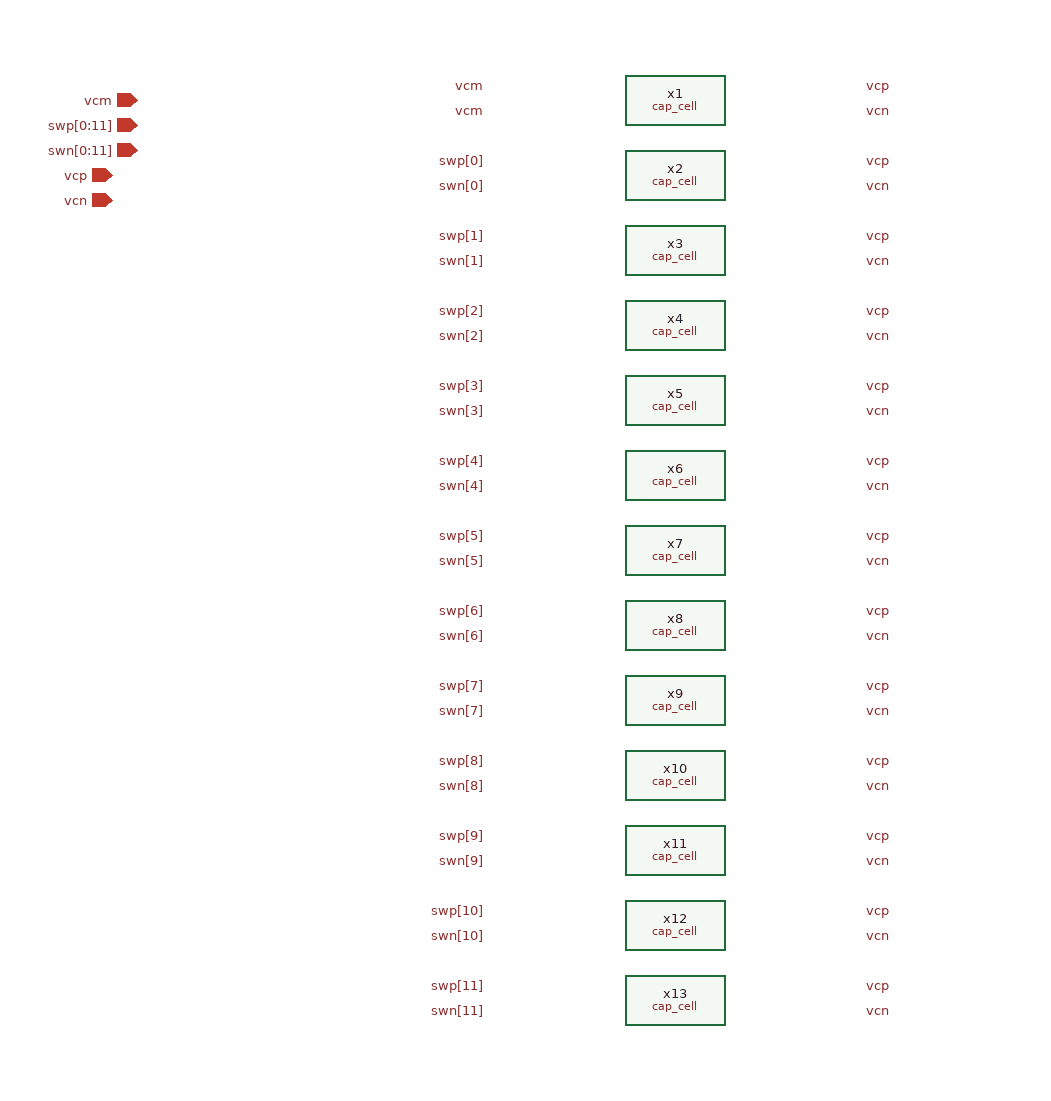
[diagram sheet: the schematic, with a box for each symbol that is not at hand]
v {xschem version=3.4.5 file_version=1.2
}
G {}
K {}
V {}
S {}
E {}
C {cap_cell.sym} 650 -880 0 0 {name=x1 dim=dim_unit num=1}
C {cap_cell.sym} 650 -820 0 0 {name=x2 dim=dim_unit num=1}
C {cap_cell.sym} 650 -760 0 0 {name=x3 dim=dim_unit num=2}
C {cap_cell.sym} 650 -700 0 0 {name=x4 dim=dim_unit num=4}
C {cap_cell.sym} 650 -640 0 0 {name=x5 dim=dim_unit num=8}
C {cap_cell.sym} 650 -580 0 0 {name=x6 dim=dim_unit num=16}
C {cap_cell.sym} 650 -520 0 0 {name=x7 dim=dim_unit num=32}
C {cap_cell.sym} 650 -460 0 0 {name=x8 dim=dim_unit num=64}
C {cap_cell.sym} 650 -400 0 0 {name=x9 dim=dim_unit num=128}
C {cap_cell.sym} 650 -340 0 0 {name=x10 dim=dim_unit num=256}
C {cap_cell.sym} 650 -280 0 0 {name=x11 dim=dim_unit num=512}
C {cap_cell.sym} 650 -220 0 0 {name=x12 dim=dim_unit num=1024}
C {cap_cell.sym} 650 -160 0 0 {name=x13 dim=dim_unit num=2048}
C {lab_wire.sym} 500 -890 0 0 {name=p1 sig_type=std_logic lab=vcm}
C {lab_wire.sym} 500 -870 0 0 {name=p2 sig_type=std_logic lab=vcm}
C {lab_wire.sym} 500 -830 0 0 {name=p3 sig_type=std_logic lab=swp[0]}
C {lab_wire.sym} 500 -810 0 0 {name=p4 sig_type=std_logic lab=swn[0]}
C {lab_wire.sym} 500 -770 0 0 {name=p5 sig_type=std_logic lab=swp[1]}
C {lab_wire.sym} 500 -750 0 0 {name=p6 sig_type=std_logic lab=swn[1]}
C {lab_wire.sym} 500 -710 0 0 {name=p7 sig_type=std_logic lab=swp[2]}
C {lab_wire.sym} 500 -690 0 0 {name=p8 sig_type=std_logic lab=swn[2]}
C {lab_wire.sym} 500 -650 0 0 {name=p9 sig_type=std_logic lab=swp[3]}
C {lab_wire.sym} 500 -630 0 0 {name=p10 sig_type=std_logic lab=swn[3]}
C {lab_wire.sym} 500 -590 0 0 {name=p11 sig_type=std_logic lab=swp[4]}
C {lab_wire.sym} 500 -570 0 0 {name=p12 sig_type=std_logic lab=swn[4]}
C {lab_wire.sym} 500 -530 0 0 {name=p13 sig_type=std_logic lab=swp[5]}
C {lab_wire.sym} 500 -510 0 0 {name=p14 sig_type=std_logic lab=swn[5]}
C {lab_wire.sym} 500 -470 0 0 {name=p15 sig_type=std_logic lab=swp[6]}
C {lab_wire.sym} 500 -450 0 0 {name=p16 sig_type=std_logic lab=swn[6]}
C {lab_wire.sym} 500 -410 0 0 {name=p17 sig_type=std_logic lab=swp[7]}
C {lab_wire.sym} 500 -390 0 0 {name=p18 sig_type=std_logic lab=swn[7]}
C {lab_wire.sym} 500 -350 0 0 {name=p19 sig_type=std_logic lab=swp[8]}
C {lab_wire.sym} 500 -330 0 0 {name=p20 sig_type=std_logic lab=swn[8]}
C {lab_wire.sym} 500 -290 0 0 {name=p21 sig_type=std_logic lab=swp[9]}
C {lab_wire.sym} 500 -270 0 0 {name=p22 sig_type=std_logic lab=swn[9]}
C {lab_wire.sym} 500 -230 0 0 {name=p23 sig_type=std_logic lab=swp[10]}
C {lab_wire.sym} 500 -210 0 0 {name=p24 sig_type=std_logic lab=swn[10]}
C {lab_wire.sym} 500 -170 0 0 {name=p25 sig_type=std_logic lab=swp[11]}
C {lab_wire.sym} 500 -150 0 0 {name=p26 sig_type=std_logic lab=swn[11]}
C {lab_wire.sym} 800 -890 0 1 {name=p27 sig_type=std_logic lab=vcp}
C {lab_wire.sym} 800 -870 0 1 {name=p28 sig_type=std_logic lab=vcn}
C {lab_wire.sym} 800 -830 0 1 {name=p29 sig_type=std_logic lab=vcp}
C {lab_wire.sym} 800 -810 0 1 {name=p30 sig_type=std_logic lab=vcn}
C {lab_wire.sym} 800 -770 0 1 {name=p31 sig_type=std_logic lab=vcp}
C {lab_wire.sym} 800 -750 0 1 {name=p32 sig_type=std_logic lab=vcn}
C {lab_wire.sym} 800 -710 0 1 {name=p33 sig_type=std_logic lab=vcp}
C {lab_wire.sym} 800 -690 0 1 {name=p34 sig_type=std_logic lab=vcn}
C {lab_wire.sym} 800 -650 0 1 {name=p35 sig_type=std_logic lab=vcp}
C {lab_wire.sym} 800 -630 0 1 {name=p36 sig_type=std_logic lab=vcn}
C {lab_wire.sym} 800 -590 0 1 {name=p37 sig_type=std_logic lab=vcp}
C {lab_wire.sym} 800 -570 0 1 {name=p38 sig_type=std_logic lab=vcn}
C {lab_wire.sym} 800 -530 0 1 {name=p39 sig_type=std_logic lab=vcp}
C {lab_wire.sym} 800 -510 0 1 {name=p40 sig_type=std_logic lab=vcn}
C {lab_wire.sym} 800 -470 0 1 {name=p41 sig_type=std_logic lab=vcp}
C {lab_wire.sym} 800 -450 0 1 {name=p42 sig_type=std_logic lab=vcn}
C {lab_wire.sym} 800 -410 0 1 {name=p43 sig_type=std_logic lab=vcp}
C {lab_wire.sym} 800 -390 0 1 {name=p44 sig_type=std_logic lab=vcn}
C {lab_wire.sym} 800 -350 0 1 {name=p45 sig_type=std_logic lab=vcp}
C {lab_wire.sym} 800 -330 0 1 {name=p46 sig_type=std_logic lab=vcn}
C {lab_wire.sym} 800 -290 0 1 {name=p47 sig_type=std_logic lab=vcp}
C {lab_wire.sym} 800 -270 0 1 {name=p48 sig_type=std_logic lab=vcn}
C {lab_wire.sym} 800 -230 0 1 {name=p49 sig_type=std_logic lab=vcp}
C {lab_wire.sym} 800 -210 0 1 {name=p50 sig_type=std_logic lab=vcn}
C {lab_wire.sym} 800 -170 0 1 {name=p51 sig_type=std_logic lab=vcp}
C {lab_wire.sym} 800 -150 0 1 {name=p52 sig_type=std_logic lab=vcn}
C {ipin.sym} 220 -860 0 0 {name=p53 lab=swp[0:11]}
C {ipin.sym} 220 -880 0 0 {name=p54 lab=vcm}
C {ipin.sym} 220 -840 0 0 {name=p55 lab=swn[0:11]}
C {iopin.sym} 200 -820 0 0 {name=p56 lab=vcp}
C {iopin.sym} 200 -800 0 0 {name=p57 lab=vcn}
